VERSION 5.7 ;
  NOWIREEXTENSIONATPIN ON ;
  DIVIDERCHAR "/" ;
  BUSBITCHARS "[]" ;
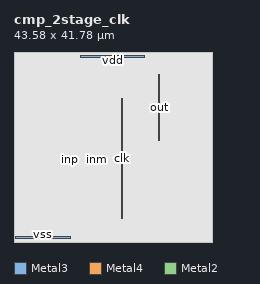
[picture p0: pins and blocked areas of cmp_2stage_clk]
MACRO cmp_2stage_clk
  CLASS BLOCK ;
  FOREIGN cmp_2stage_clk ;
  ORIGIN 21.900 3.940 ;
  SIZE 43.580 BY 41.780 ;
  PIN out
    ANTENNAGATEAREA 1.920000 ;
    ANTENNADIFFAREA 3.420000 ;
    PORT
      LAYER Metal3 ;
        RECT 9.860 18.340 10.140 32.900 ;
    END
  END out
  PIN clk
    ANTENNAGATEAREA 4.480000 ;
    PORT
      LAYER Metal4 ;
        RECT 1.700 1.280 1.980 27.520 ;
    END
  END clk
  PIN inm
    ANTENNAGATEAREA 2.400000 ;
    PORT
      LAYER Metal2 ;
        RECT -3.870 14.150 -3.590 14.430 ;
    END
  END inm
  PIN inp
    ANTENNAGATEAREA 2.400000 ;
    PORT
      LAYER Metal2 ;
        RECT -9.730 14.150 -9.450 14.430 ;
    END
  END inp
  PIN vss
    ANTENNADIFFAREA 43.833599 ;
    PORT
      LAYER Metal3 ;
        RECT -21.480 -3.220 -9.520 -2.660 ;
    END
  END vss
  PIN vdd
    ANTENNADIFFAREA 48.715199 ;
    PORT
      LAYER Metal3 ;
        RECT -7.200 36.560 6.800 37.120 ;
    END
  END vdd
  OBS
      LAYER Nwell ;
        RECT -18.680 0.000 18.680 33.670 ;
      LAYER Metal1 ;
        RECT -18.450 0.210 18.450 33.460 ;
      LAYER Metal2 ;
        RECT -18.450 14.730 18.450 33.460 ;
        RECT -18.450 13.850 -10.030 14.730 ;
        RECT -9.150 13.850 -4.170 14.730 ;
        RECT -3.290 13.850 18.450 14.730 ;
        RECT -18.450 0.210 18.450 13.850 ;
      LAYER Metal3 ;
        RECT -21.900 36.260 -7.500 37.120 ;
        RECT 7.100 36.260 21.500 37.120 ;
        RECT -21.900 33.200 21.500 36.260 ;
        RECT -21.900 18.040 9.560 33.200 ;
        RECT 10.440 18.040 21.500 33.200 ;
        RECT -21.900 -2.360 21.500 18.040 ;
        RECT -21.900 -2.660 -21.780 -2.360 ;
        RECT -21.900 -2.800 -21.480 -2.660 ;
        RECT -21.900 -3.080 -21.760 -2.800 ;
        RECT -21.900 -3.220 -21.480 -3.080 ;
        RECT -9.220 -3.220 21.500 -2.360 ;
      LAYER Metal4 ;
        RECT -21.870 27.820 21.470 37.090 ;
        RECT -21.870 0.980 1.400 27.820 ;
        RECT 2.280 0.980 21.470 27.820 ;
        RECT -21.870 -3.220 21.470 0.980 ;
      LAYER Metal5 ;
        RECT -21.870 -3.940 21.680 37.840 ;
  END
END cmp_2stage_clk
END LIBRARY

